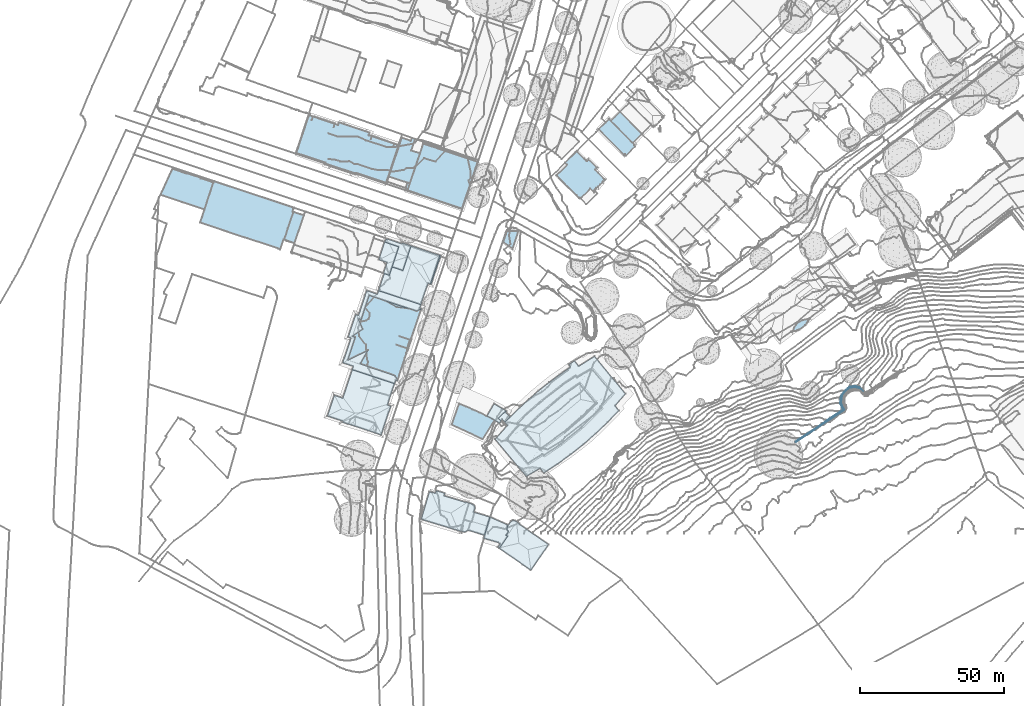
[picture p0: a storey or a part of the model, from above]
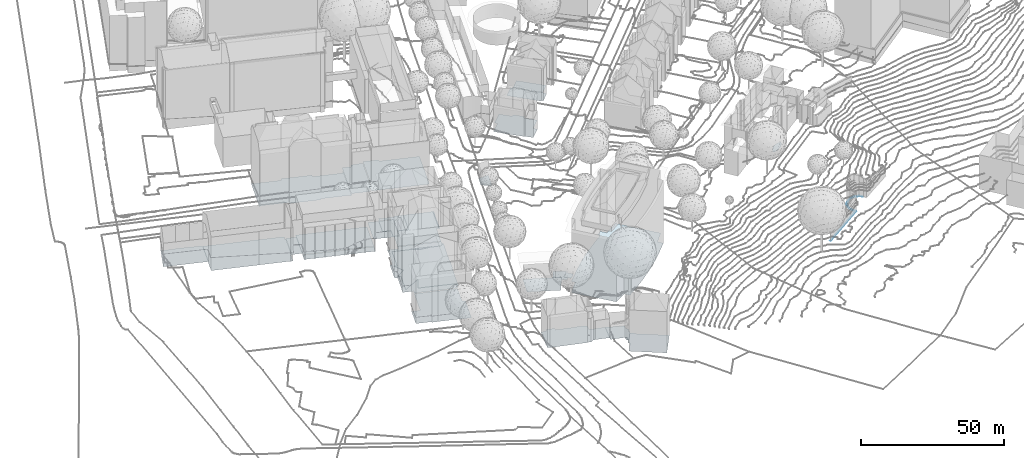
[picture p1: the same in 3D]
Properties of the parts of a building model (IFC2X3)

# File
Description: ViewDefinition [CoordinationView]
Time: 2024-08-21T15:45:22
Written by: TpxIfclib v0.1
Made in: TpxIfclib v0.1

# IfcFooting (282)
In: Topoexport Data
PredefinedType: STRIP_FOOTING
Name
238 x Floor 0
11 x Floor 1
3 x Floor 2
2 x Floor 3
2 x Floor 4
2 x Floor 5
2 x Floor 6
2 x Floor 7
2 x Floor 8
2 x Floor 9
Floor 10
Floor 11
Floor 12
Floor 13
Floor 14
Floor 15
Floor 16
Floor 17
Floor 18
Floor 19
Floor 20
Floor 21
Floor 22
Floor 23
Floor 24
Floor 25
